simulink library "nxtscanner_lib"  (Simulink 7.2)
settings: Solver=ode45  StartTime=0.0  StopTime=10.0  RelTol=1e-3
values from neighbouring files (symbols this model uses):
  ERROR_001_SOUND_FREQ = 880    [mode_control_prm.m]
  ERROR_002_SOUND_FREQ = 220    [mode_control_prm.m]
  ERROR_SOUND_DUR = 3000    [mode_control_prm.m]
  ERROR_SOUND_VOL = 20    [mode_control_prm.m]
undefined symbols (not defined in the file or in its folder): BACKLASH_ADJUST, Enum, ErrorCodeEnum, FeedModeEnum, RELEASE_TOUCH_SENSOR, SCAN_EDGE, SCAN_F_TIMEOUT, SCAN_INITIALIZE_PWM, SCAN_INITIALIZE_TIMEOUT, SCAN_L_MAX_PWM, SCAN_L_MIN_PWM, SCAN_L_TIMEOUT, SCAN_R_MAX_PWM, SCAN_R_MIN_PWM, SCAN_R_TIMEOUT, SCAN_START, ScanModeEnum

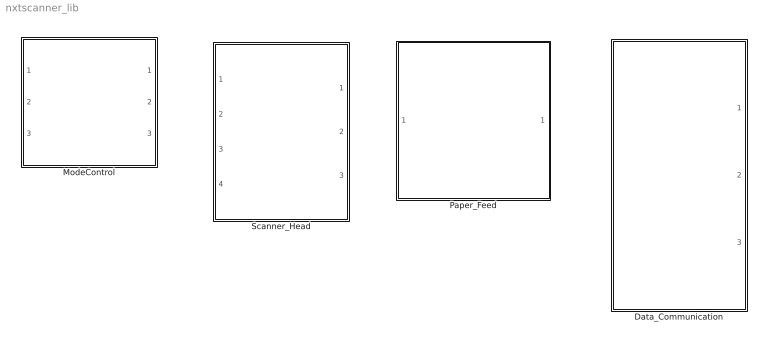
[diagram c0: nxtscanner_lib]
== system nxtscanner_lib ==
  Data_Communication : Subsystem
  ModeControl : Subsystem  TreatAsAtomicUnit=on
  Paper_Feed : Subsystem  TreatAsAtomicUnit=on
  Scanner_Head : Subsystem  TreatAsAtomicUnit=on

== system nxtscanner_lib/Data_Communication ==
  Mux : Mux  Inputs=3
  usb_communication_main : Stateflow chart
  usb_trans_data : Outport  OutDataType=sfix(16)  OutScaling=2^0
  request_event : Outport  Port=2  OutDataType=sfix(16)  OutScaling=2^0
  disconnect_event : Outport  Port=3  OutDataType=sfix(16)  OutScaling=2^0
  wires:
  usb_communication_main/5(DISCONNECT) -> disconnect_event/1
  usb_communication_main/4(COMUNICATION) -> request_event/1
  usb_communication_main/3(usb_send_data) -> Mux/3
  usb_communication_main/2(usb_send_number) -> Mux/2
  usb_communication_main/1(usb_send_status) -> Mux/1
  Mux/1 -> usb_trans_data/1

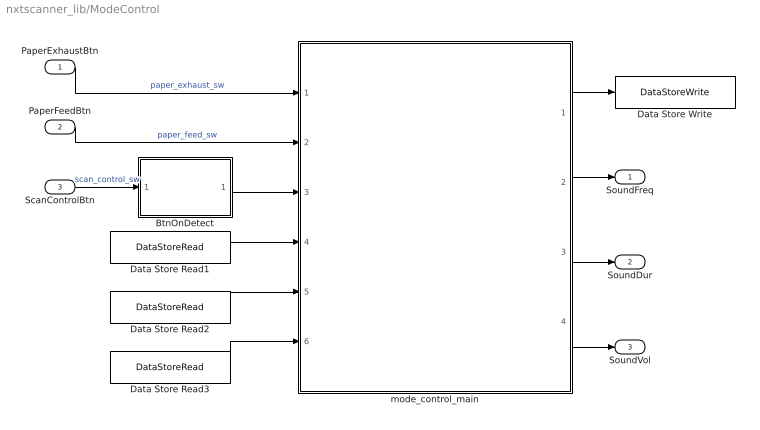
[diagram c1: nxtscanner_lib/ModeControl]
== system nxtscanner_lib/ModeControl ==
  PaperExhaustBtn : Inport
  PaperFeedBtn : Inport  Port=2
  ScanControlBtn : Inport  Port=3
  BtnOnDetect : Subsystem  TreatAsAtomicUnit=on
  Data Store Read1 : DataStoreRead  DataStoreName=ErrorCode  SampleTime=-1
  Data Store Read2 : DataStoreRead  DataStoreName=ScanMode  SampleTime=-1
  Data Store Read3 : DataStoreRead  DataStoreName=FeedMode  SampleTime=-1
  Data Store Write : DataStoreWrite  DataStoreName=ControlMode  SampleTime=-1
  mode_control_main : Stateflow chart
  SoundFreq : Outport  OutDataType=sfix(16)  OutScaling=2^0
  SoundDur : Outport  Port=2  OutDataType=sfix(16)  OutScaling=2^0
  SoundVol : Outport  Port=3  OutDataType=sfix(16)  OutScaling=2^0
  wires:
  Data Store Read3/1 -> mode_control_main/6(FeedMode)
  Data Store Read2/1 -> mode_control_main/5(ScanMode)
  mode_control_main/4(SoundVol) -> SoundVol/1
  mode_control_main/3(SoundDur) -> SoundDur/1
  mode_control_main/2(SoundFreq) -> SoundFreq/1
  BtnOnDetect/1(off2on) -> mode_control_main/3(ScanControl)
  ScanControlBtn/1 -> BtnOnDetect/1(button)  "scan_control_sw"
  PaperExhaustBtn/1 -> mode_control_main/1(PaperExhaustBtn)  "paper_exhaust_sw"
  PaperFeedBtn/1 -> mode_control_main/2(PaperFeedBtn)  "paper_feed_sw"
  Data Store Read1/1 -> mode_control_main/4(ErrorCode)
  mode_control_main/1(ControlMode) -> Data Store Write/1

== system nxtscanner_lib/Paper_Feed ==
  Encoder : Inport  OutDataType=sfix(16)  OutScaling=2^0
  Chart : Stateflow chart
  Counter_For_Error : Subsystem  TreatAsAtomicUnit=on
  Data Store Memory : DataStoreMemory  DataStoreName=ROTOR_FLAG  ReadBeforeWriteMsg=warning  WriteAfterWriteMsg=warning  WriteAfterReadMsg=warning  DataType=boolean  OutDataType=sfix(16)  OutScaling=2^0  OutDataTypeStr=boolean
  Data Store Memory1 : DataStoreMemory  DataStoreName=ROTOR_INIT  ReadBeforeWriteMsg=warning  WriteAfterWriteMsg=warning  WriteAfterReadMsg=warning  DataType=int32  OutDataType=sfix(16)  OutScaling=2^0  OutDataTypeStr=int32
  Data Store Write : DataStoreWrite  DataStoreName=ErrorCode  SampleTime=-1
  PWM : Outport  OutDataType=sfix(16)  OutScaling=2^0
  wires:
  Counter_For_Error/1(ErrorCode) -> Data Store Write/1
  Chart/2(ErrDetect) -> Counter_For_Error/Enable
  Encoder/1 -> Counter_For_Error/1(Encoder), Chart/1(Encoder)
  Chart/1(PWM) -> PWM/1

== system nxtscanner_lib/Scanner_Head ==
  Touch : Inport
  Encoder : Inport  Port=2
  LightSensor : Inport  Port=3
  SystemClock : Inport  Port=4
  scanner_head_main : Stateflow chart
  PWM : Outport  OutDataType=sfix(16)  OutScaling=2^0
  now_position : Outport  Port=2  OutDataType=sfix(16)  OutScaling=2^0
  encoder_base : Outport  Port=3  OutDataType=sfix(16)  OutScaling=2^0
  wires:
  SystemClock/1 -> scanner_head_main/4(system_clock_in)  "systick_ms"
  scanner_head_main/3(encoder_base) -> encoder_base/1
  scanner_head_main/2(now_position) -> now_position/1
  scanner_head_main/1(pwm_out) -> PWM/1
  LightSensor/1 -> scanner_head_main/3(lightsensor_in)  "light_data"
  Encoder/1 -> scanner_head_main/2(encoder_in)  "scanner_head_rev"
  Touch/1 -> scanner_head_main/1(touch_in)  "scanner_head_reset_sw"

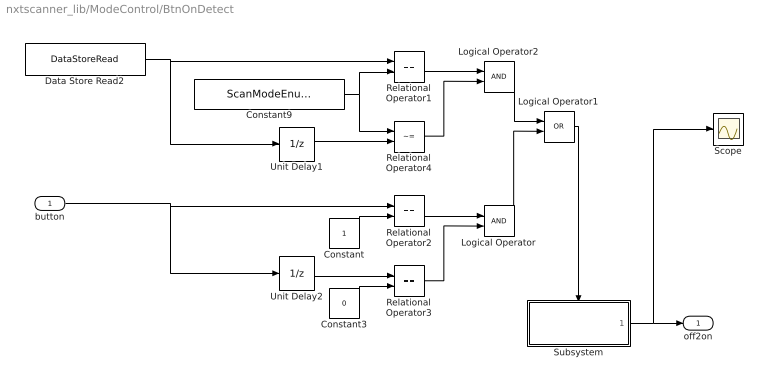
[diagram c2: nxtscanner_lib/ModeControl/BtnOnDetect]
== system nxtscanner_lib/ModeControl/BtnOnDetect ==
  button : Inport  OutDataType=sfix(16)  OutScaling=2^0
  Constant : Constant  OutDataTypeMode=uint8  OutDataType=sfix(16)  OutScaling=2^0  OutDataTypeStr=uint8
  Constant3 : Constant  Value=0  OutDataTypeMode=uint8  OutDataType=sfix(16)  OutScaling=2^0  OutDataTypeStr=uint8
  Constant9 : Constant  Value=ScanModeEnum.SCAN_INIT  OutDataTypeMode=Specify via dialog  OutDataType=Enum:ScanModeEnum  ConRadixGroup=Best Precision: Vector-wise  OutDataTypeStr=Enum:ScanModeEnum
  Data Store Read2 : DataStoreRead  DataStoreName=ScanMode  SampleTime=-1
  Logical Operator : Logic  AllPortsSameDT=off  OutDataTypeMode=boolean  OutDataTypeStr=boolean
  Logical Operator1 : Logic  Operator=OR  AllPortsSameDT=off  OutDataTypeMode=boolean  OutDataTypeStr=boolean
  Logical Operator2 : Logic  AllPortsSameDT=off  OutDataTypeMode=boolean  OutDataTypeStr=boolean
  Relational Operator1 : RelationalOperator  Operator===  LogicOutDataTypeMode=boolean  OutDataTypeStr=boolean
  Relational Operator2 : RelationalOperator  Operator===  LogicOutDataTypeMode=boolean  OutDataTypeStr=boolean
  Relational Operator3 : RelationalOperator  Operator===  LogicOutDataTypeMode=boolean  OutDataTypeStr=boolean
  Relational Operator4 : RelationalOperator  Operator=~=  LogicOutDataTypeMode=boolean  OutDataTypeStr=boolean
  Scope : Scope
  Subsystem : Subsystem  TreatAsAtomicUnit=on
  Unit Delay1 : UnitDelay  X0=ScanModeEnum.SCAN_INIT  SampleTime=-1
  Unit Delay2 : UnitDelay  SampleTime=-1
  off2on : Outport  OutDataType=sfix(16)  OutScaling=2^0
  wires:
  Subsystem/1(Out1) -> off2on/1, Scope/1
  Unit Delay1/1 -> Relational Operator4/2
  button/1 -> Relational Operator2/1, Unit Delay2/1
  Unit Delay2/1 -> Relational Operator3/1
  Relational Operator2/1 -> Logical Operator/1
  Relational Operator3/1 -> Logical Operator/2
  Constant/1 -> Relational Operator2/2
  Constant3/1 -> Relational Operator3/2
  Logical Operator1/1 -> Subsystem/Enable
  Logical Operator/1 -> Logical Operator1/2
  Data Store Read2/1 -> Unit Delay1/1, Relational Operator1/1
  Relational Operator1/1 -> Logical Operator2/1
  Logical Operator2/1 -> Logical Operator1/1
  Constant9/1 -> Relational Operator4/1, Relational Operator1/2
  Relational Operator4/1 -> Logical Operator2/2

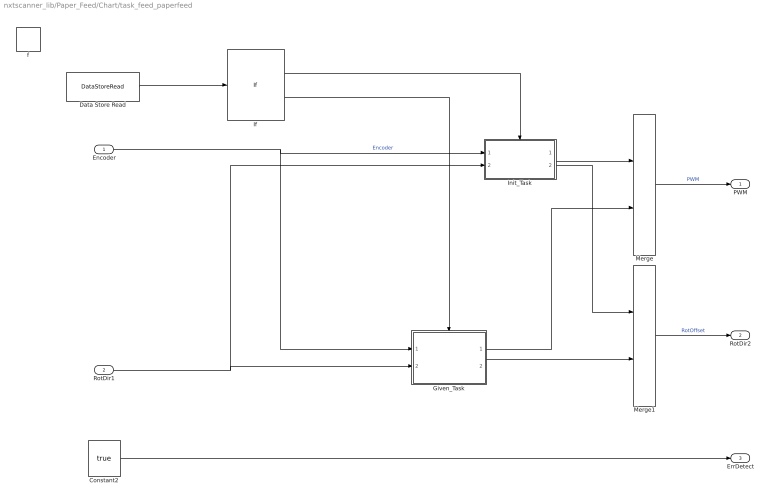
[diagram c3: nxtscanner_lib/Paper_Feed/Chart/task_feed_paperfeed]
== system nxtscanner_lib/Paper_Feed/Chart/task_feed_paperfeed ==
  Encoder : Inport  OutDataType=sfix(16)  OutScaling=2^0
  RotDir1 : Inport  Port=2  DataType=boolean  OutDataTypeStr=boolean
  f : TriggerPort  TriggerType=function-call  StatesWhenEnabling=reset
  Constant2 : Constant  Value=true  OutDataTypeMode=boolean  OutDataType=sfix(16)  OutScaling=2^0  OutDataTypeStr=boolean  SampleTime=-1
  Data Store Read : DataStoreRead  DataStoreName=ROTOR_FLAG  SampleTime=-1
  Given_Task : Subsystem  TreatAsAtomicUnit=on
  If : If  IfExpression=~u1
  Init_Task : Subsystem  TreatAsAtomicUnit=on
  Merge : Merge
  Merge1 : Merge
  PWM : Outport  OutDataType=sfix(16)  OutScaling=2^0
  RotDir2 : Outport  Port=2
  ErrDetect : Outport  Port=3  InitialOutput=0
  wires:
  Constant2/1 -> ErrDetect/1
  Init_Task/2(RotOffset1) -> Merge1/1
  Given_Task/1(PWM) -> Merge/2
  Given_Task/2(RotOffset1) -> Merge1/2
  Merge1/1 -> RotDir2/1  "RotOffset"
  RotDir1/1 -> Init_Task/2(RotOffset), Given_Task/2(RotOffset)
  Merge/1 -> PWM/1  "PWM"
  Init_Task/1(PWM) -> Merge/1
  Encoder/1 -> Given_Task/1(Encoder), Init_Task/1(Encoder)  "Encoder"
  If/2 -> Given_Task/Action
  If/1 -> Init_Task/Action
  Data Store Read/1 -> If/1

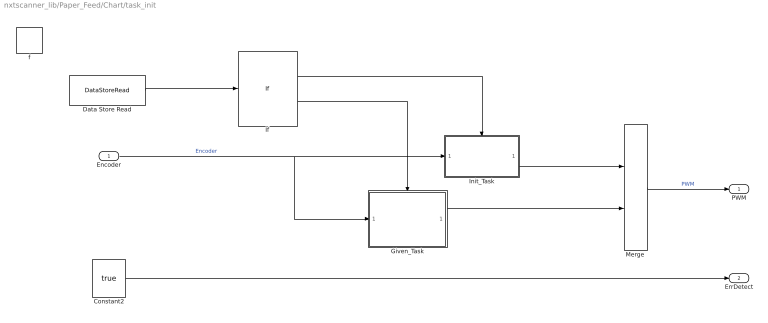
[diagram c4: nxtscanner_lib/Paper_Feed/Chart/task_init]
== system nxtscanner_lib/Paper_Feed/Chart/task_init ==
  Encoder : Inport  OutDataType=sfix(16)  OutScaling=2^0
  f : TriggerPort  TriggerType=function-call  StatesWhenEnabling=reset
  Constant2 : Constant  Value=true  OutDataTypeMode=boolean  OutDataType=sfix(16)  OutScaling=2^0  OutDataTypeStr=boolean  SampleTime=-1
  Data Store Read : DataStoreRead  DataStoreName=ROTOR_FLAG  SampleTime=-1
  Given_Task : Subsystem  TreatAsAtomicUnit=on
  If : If  IfExpression=~u1
  Init_Task : Subsystem  TreatAsAtomicUnit=on
  Merge : Merge
  PWM : Outport
  ErrDetect : Outport  Port=2  InitialOutput=0
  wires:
  Constant2/1 -> ErrDetect/1
  Given_Task/1(PWM) -> Merge/2
  Merge/1 -> PWM/1  "PWM"
  Init_Task/1(PWM) -> Merge/1
  Encoder/1 -> Given_Task/1(Encoder), Init_Task/1(Encoder)  "Encoder"
  If/2 -> Given_Task/Action
  If/1 -> Init_Task/Action
  Data Store Read/1 -> If/1

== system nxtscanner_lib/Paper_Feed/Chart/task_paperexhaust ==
  f : TriggerPort  TriggerType=function-call  StatesWhenEnabling=reset
  Constant : Constant  Value=-100  OutDataTypeMode=int8  OutDataType=sfix(16)  OutScaling=2^0  OutDataTypeStr=int8  SampleTime=-1
  Constant1 : Constant  Value=true  OutDataTypeMode=boolean  OutDataType=sfix(16)  OutScaling=2^0  OutDataTypeStr=boolean  SampleTime=-1
  Constant2 : Constant  Value=true  OutDataTypeMode=boolean  OutDataType=sfix(16)  OutScaling=2^0  OutDataTypeStr=boolean  SampleTime=-1
  PWM : Outport  OutDataType=sfix(16)  OutScaling=2^0  InitialOutput=0
  RotDir : Outport  Port=2  InitialOutput=0
  ErrDetect : Outport  Port=3  InitialOutput=0
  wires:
  Constant2/1 -> ErrDetect/1
  Constant1/1 -> RotDir/1
  Constant/1 -> PWM/1  "PWM"

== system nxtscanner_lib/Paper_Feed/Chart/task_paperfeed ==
  f : TriggerPort  TriggerType=function-call  StatesWhenEnabling=reset
  Constant : Constant  Value=100  OutDataTypeMode=int8  OutDataType=sfix(16)  OutScaling=2^0  OutDataTypeStr=int8  SampleTime=-1
  Constant1 : Constant  Value=false  OutDataTypeMode=boolean  OutDataType=sfix(16)  OutScaling=2^0  OutDataTypeStr=boolean  SampleTime=-1
  Constant2 : Constant  Value=true  OutDataTypeMode=boolean  OutDataType=sfix(16)  OutScaling=2^0  OutDataTypeStr=boolean  SampleTime=-1
  PWM : Outport  OutDataType=sfix(16)  OutScaling=2^0  InitialOutput=0
  RotDir : Outport  Port=2  InitialOutput=0
  ErrDetect : Outport  Port=3  InitialOutput=0
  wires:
  Constant2/1 -> ErrDetect/1
  Constant1/1 -> RotDir/1
  Constant/1 -> PWM/1  "PWM"

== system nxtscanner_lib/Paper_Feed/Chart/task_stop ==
  f : TriggerPort  TriggerType=function-call  StatesWhenEnabling=reset
  Constant : Constant  Value=0  OutDataTypeMode=int8  OutDataType=sfix(16)  OutScaling=2^0  OutDataTypeStr=int8  SampleTime=-1
  Constant2 : Constant  Value=false  OutDataTypeMode=boolean  OutDataType=sfix(16)  OutScaling=2^0  OutDataTypeStr=boolean  SampleTime=-1
  PWM : Outport  OutDataType=sfix(16)  OutScaling=2^0  InitialOutput=0
  ErrDetect : Outport  Port=2  InitialOutput=0
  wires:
  Constant2/1 -> ErrDetect/1
  Constant/1 -> PWM/1  "PWM"

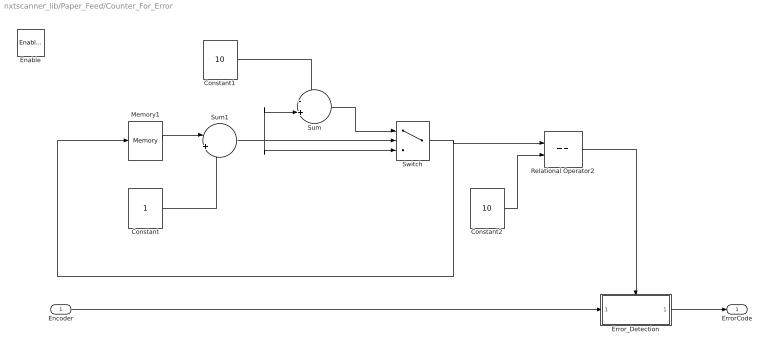
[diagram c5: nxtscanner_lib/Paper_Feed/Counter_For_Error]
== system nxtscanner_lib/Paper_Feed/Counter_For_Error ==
  Encoder : Inport  OutDataType=sfix(16)  OutScaling=2^0
  Enable : EnablePort  StatesWhenEnabling=reset
  Constant : Constant  OutDataTypeMode=uint8  OutDataType=sfix(16)  OutScaling=2^0  OutDataTypeStr=uint8  SampleTime=-1
  Constant1 : Constant  Value=10  OutDataTypeMode=uint8  OutDataType=sfix(16)  OutScaling=2^0  OutDataTypeStr=uint8  SampleTime=-1
  Constant2 : Constant  Value=10  OutDataTypeMode=uint8  OutDataType=sfix(16)  OutScaling=2^0  OutDataTypeStr=uint8  SampleTime=-1
  Error_Detection : Subsystem  TreatAsAtomicUnit=on
  Memory1 : Memory  InheritSampleTime=on
  Relational Operator2 : RelationalOperator  Operator===  LogicOutDataTypeMode=boolean  OutDataTypeStr=boolean
  Sum : Sum  Inputs=-+|  OutDataType=sfix(16)  OutScaling=2^0
  Sum1 : Sum  Inputs=|++  OutDataType=sfix(16)  OutScaling=2^0
  Switch : Switch  Criteria=u2 > Threshold  Threshold=10  OutDataTypeMode=uint8  OutDataType=sfix(16)  OutScaling=2^0  OutDataTypeStr=uint8
  ErrorCode : Outport  OutDataType=sfix(16)  OutScaling=2^0  InitialOutput=ErrorCodeEnum.NO_ERROR
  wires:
  Constant2/1 -> Relational Operator2/2
  Sum/1 -> Switch/1
  Sum1/1 -> Switch/3, Sum/2, Switch/2
  Constant1/1 -> Sum/1
  Switch/1 -> Memory1/1, Relational Operator2/1
  Memory1/1 -> Sum1/1
  Relational Operator2/1 -> Error_Detection/Trigger
  Error_Detection/1(ErrorCode) -> ErrorCode/1
  Encoder/1 -> Error_Detection/1(Encoder)
  Constant/1 -> Sum1/2

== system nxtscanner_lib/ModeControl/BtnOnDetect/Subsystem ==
  Enable : EnablePort
  Constant1 : Constant  OutDataTypeMode=uint8  OutDataType=sfix(16)  OutScaling=2^0  OutDataTypeStr=uint8
  Constant3 : Constant  Value=0  OutDataTypeMode=uint8  OutDataType=sfix(16)  OutScaling=2^0  OutDataTypeStr=uint8
  Switch : Switch  Threshold=0.5
  Unit Delay2 : UnitDelay  Orientation=left  SampleTime=-1
  Out1 : Outport  OutDataType=sfix(16)  OutScaling=2^0
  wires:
  Constant3/1 -> Switch/1
  Unit Delay2/1 -> Switch/2
  Constant1/1 -> Switch/3
  Switch/1 -> Unit Delay2/1, Out1/1

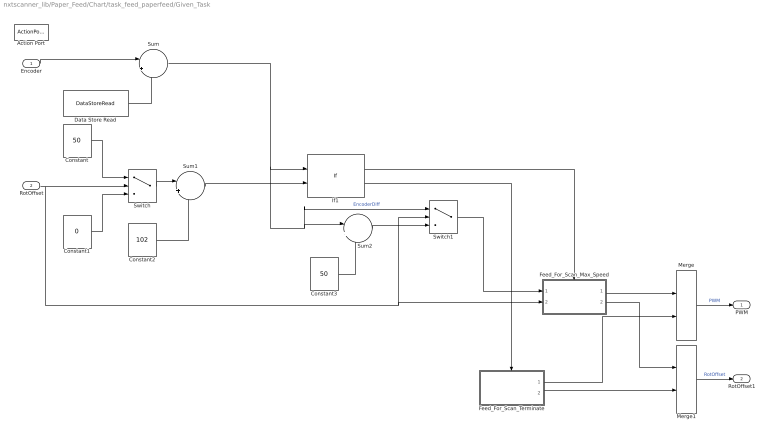
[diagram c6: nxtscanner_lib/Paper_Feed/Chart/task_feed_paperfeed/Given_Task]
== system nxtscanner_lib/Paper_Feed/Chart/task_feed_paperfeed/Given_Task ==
  Encoder : Inport  OutDataType=sfix(16)  OutScaling=2^0
  RotOffset : Inport  Port=2  OutDataType=sfix(16)  OutScaling=2^0
  Action Port : ActionPort
  Constant : Constant  Value=50  OutDataTypeMode=int32  OutDataType=sfix(16)  OutScaling=2^0  OutDataTypeStr=int32  SampleTime=-1
  Constant1 : Constant  Value=0  OutDataTypeMode=int32  OutDataType=sfix(16)  OutScaling=2^0  OutDataTypeStr=int32  SampleTime=-1
  Constant2 : Constant  Value=102  OutDataTypeMode=int32  OutDataType=sfix(16)  OutScaling=2^0  OutDataTypeStr=int32  SampleTime=-1
  Constant3 : Constant  Value=50  OutDataTypeMode=int32  OutDataType=sfix(16)  OutScaling=2^0  OutDataTypeStr=int32  SampleTime=-1
  Data Store Read : DataStoreRead  DataStoreName=ROTOR_INIT  SampleTime=-1
  Feed_For_Scan_Max_Speed : Subsystem  TreatAsAtomicUnit=on
  Feed_For_Scan_Terminate : Subsystem  TreatAsAtomicUnit=on
  If1 : If  NumInputs=2  IfExpression=u1 < u2
  Merge : Merge
  Merge1 : Merge
  Sum : Sum  Inputs=|+-  OutDataType=sfix(16)  OutScaling=2^0
  Sum1 : Sum  Inputs=|++  OutDataType=sfix(16)  OutScaling=2^0
  Sum2 : Sum  Inputs=|++  OutDataType=sfix(16)  OutScaling=2^0
  Switch : Switch  Criteria=u2 ~= 0  OutDataType=sfix(16)  OutScaling=2^0
  Switch1 : Switch  Criteria=u2 ~= 0  OutDataType=sfix(16)  OutScaling=2^0
  PWM : Outport  OutDataType=sfix(16)  OutScaling=2^0
  RotOffset1 : Outport  Port=2  OutDataType=sfix(16)  OutScaling=2^0
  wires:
  Sum2/1 -> Switch1/3
  Switch1/1 -> Feed_For_Scan_Max_Speed/1(EncoderDiff)
  Constant3/1 -> Sum2/2
  Sum1/1 -> If1/2
  Feed_For_Scan_Terminate/2(RotOffset) -> Merge1/2
  Feed_For_Scan_Max_Speed/2(RotOffset1) -> Merge1/1
  Feed_For_Scan_Terminate/1(PWM) -> Merge/2
  Feed_For_Scan_Max_Speed/1(PWM) -> Merge/1
  Constant1/1 -> Switch/3
  Constant/1 -> Switch/1
  Merge1/1 -> RotOffset1/1  "RotOffset"
  Constant2/1 -> Sum1/2
  Switch/1 -> Sum1/1
  RotOffset/1 -> Switch1/2, Feed_For_Scan_Max_Speed/2(RotOffset), Switch/2
  Merge/1 -> PWM/1  "PWM"
  If1/2 -> Feed_For_Scan_Terminate/Action
  If1/1 -> Feed_For_Scan_Max_Speed/Action
  Encoder/1 -> Sum/1
  Sum/1 -> Switch1/1, Sum2/1, If1/1  "EncoderDiff"
  Data Store Read/1 -> Sum/2

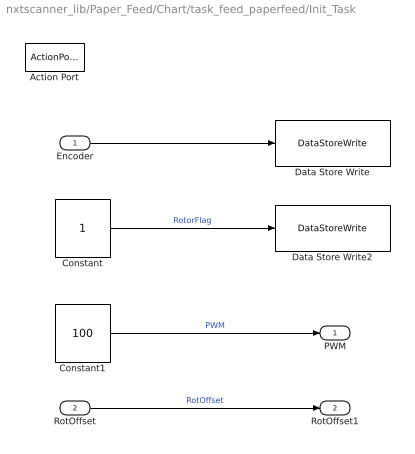
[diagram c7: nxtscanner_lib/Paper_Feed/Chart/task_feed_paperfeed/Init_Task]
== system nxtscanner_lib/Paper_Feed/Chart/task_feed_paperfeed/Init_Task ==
  Encoder : Inport  OutDataType=sfix(16)  OutScaling=2^0
  RotOffset : Inport  Port=2  OutDataType=sfix(16)  OutScaling=2^0
  Action Port : ActionPort
  Constant : Constant  OutDataTypeMode=boolean  OutDataType=sfix(16)  OutScaling=2^0  OutDataTypeStr=boolean  SampleTime=-1
  Constant1 : Constant  Value=100  OutDataTypeMode=int8  OutDataType=sfix(16)  OutScaling=2^0  OutDataTypeStr=int8  SampleTime=-1
  Data Store Write : DataStoreWrite  DataStoreName=ROTOR_INIT  SampleTime=-1
  Data Store Write2 : DataStoreWrite  DataStoreName=ROTOR_FLAG  SampleTime=-1
  PWM : Outport  OutDataType=sfix(16)  OutScaling=2^0  InitialOutput=100
  RotOffset1 : Outport  Port=2
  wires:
  RotOffset/1 -> RotOffset1/1  "RotOffset"
  Constant1/1 -> PWM/1  "PWM"
  Constant/1 -> Data Store Write2/1  "RotorFlag"
  Encoder/1 -> Data Store Write/1

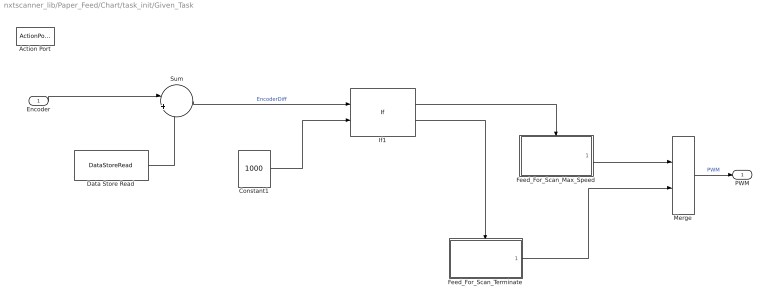
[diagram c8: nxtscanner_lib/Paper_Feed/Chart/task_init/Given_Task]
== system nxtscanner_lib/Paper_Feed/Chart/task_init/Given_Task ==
  Encoder : Inport  OutDataType=sfix(16)  OutScaling=2^0
  Action Port : ActionPort
  Constant1 : Constant  Value=1000  OutDataTypeMode=int32  OutDataType=sfix(16)  OutScaling=2^0  OutDataTypeStr=int32  SampleTime=-1
  Data Store Read : DataStoreRead  DataStoreName=ROTOR_INIT  SampleTime=-1
  Feed_For_Scan_Max_Speed : Subsystem  TreatAsAtomicUnit=on
  Feed_For_Scan_Terminate : Subsystem  TreatAsAtomicUnit=on
  If1 : If  NumInputs=2  IfExpression=u1 < u2
  Merge : Merge
  Sum : Sum  Inputs=|+-  OutDataType=sfix(16)  OutScaling=2^0
  PWM : Outport  OutDataType=sfix(16)  OutScaling=2^0
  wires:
  Feed_For_Scan_Terminate/1(PWM) -> Merge/2
  Constant1/1 -> If1/2
  Feed_For_Scan_Max_Speed/1(PWM) -> Merge/1
  Merge/1 -> PWM/1  "PWM"
  If1/2 -> Feed_For_Scan_Terminate/Action
  If1/1 -> Feed_For_Scan_Max_Speed/Action
  Encoder/1 -> Sum/1
  Sum/1 -> If1/1  "EncoderDiff"
  Data Store Read/1 -> Sum/2

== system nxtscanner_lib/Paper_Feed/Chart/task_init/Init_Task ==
  Encoder : Inport  OutDataType=sfix(16)  OutScaling=2^0
  Action Port : ActionPort
  Constant : Constant  OutDataTypeMode=boolean  OutDataType=sfix(16)  OutScaling=2^0  OutDataTypeStr=boolean  SampleTime=-1
  Constant1 : Constant  Value=100  OutDataTypeMode=int8  OutDataType=sfix(16)  OutScaling=2^0  OutDataTypeStr=int8  SampleTime=-1
  Data Store Write : DataStoreWrite  DataStoreName=ROTOR_INIT  SampleTime=-1
  Data Store Write2 : DataStoreWrite  DataStoreName=ROTOR_FLAG  SampleTime=-1
  PWM : Outport  OutDataType=sfix(16)  OutScaling=2^0  InitialOutput=100
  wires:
  Encoder/1 -> Data Store Write/1
  Constant1/1 -> PWM/1  "PWM"
  Constant/1 -> Data Store Write2/1  "RotorFlag"

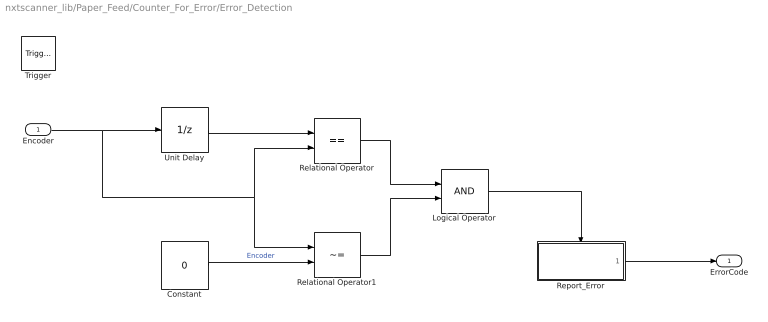
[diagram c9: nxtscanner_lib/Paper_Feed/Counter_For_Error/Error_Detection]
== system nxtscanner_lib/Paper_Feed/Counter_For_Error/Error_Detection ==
  Encoder : Inport  OutDataType=sfix(16)  OutScaling=2^0
  Trigger : TriggerPort
  Constant : Constant  Value=0  OutDataTypeMode=int8  OutDataType=sfix(16)  OutScaling=2^0  OutDataTypeStr=int8  SampleTime=-1
  Logical Operator : Logic  AllPortsSameDT=off  OutDataTypeMode=boolean  OutDataTypeStr=boolean
  Relational Operator : RelationalOperator  Operator===  LogicOutDataTypeMode=boolean  OutDataTypeStr=boolean
  Relational Operator1 : RelationalOperator  Operator=~=  LogicOutDataTypeMode=boolean  OutDataTypeStr=boolean
  Report_Error : Subsystem  TreatAsAtomicUnit=on
  Unit Delay : UnitDelay  SampleTime=-1
  ErrorCode : Outport  OutDataType=sfix(16)  OutScaling=2^0
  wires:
  Constant/1 -> Relational Operator1/2  "Encoder"
  Encoder/1 -> Relational Operator/2, Relational Operator1/1, Unit Delay/1
  Relational Operator/1 -> Logical Operator/1
  Relational Operator1/1 -> Logical Operator/2
  Unit Delay/1 -> Relational Operator/1
  Logical Operator/1 -> Report_Error/Enable
  Report_Error/1(ErrorCode) -> ErrorCode/1

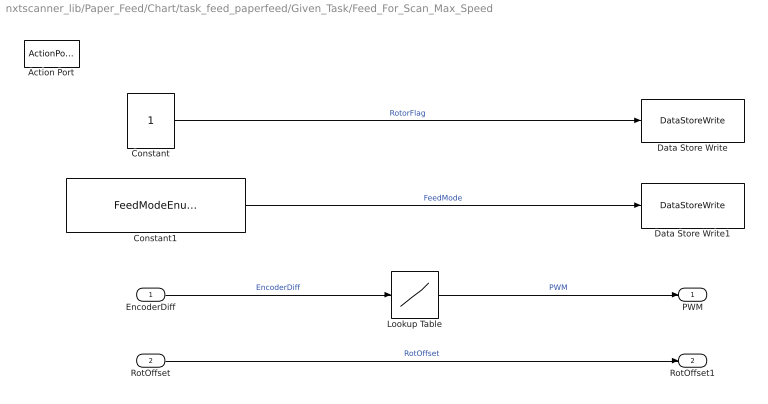
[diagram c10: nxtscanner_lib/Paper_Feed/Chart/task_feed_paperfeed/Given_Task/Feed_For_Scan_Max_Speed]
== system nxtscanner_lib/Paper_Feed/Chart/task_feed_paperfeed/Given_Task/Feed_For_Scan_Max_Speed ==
  EncoderDiff : Inport  OutDataType=sfix(16)  OutScaling=2^0
  RotOffset : Inport  Port=2  OutDataType=sfix(16)  OutScaling=2^0
  Action Port : ActionPort
  Constant : Constant  OutDataTypeMode=boolean  OutDataType=sfix(16)  OutScaling=2^0  OutDataTypeStr=boolean  SampleTime=-1
  Constant1 : Constant  Value=FeedModeEnum.FEED_PAPERFEED  OutDataTypeMode=Specify via dialog  OutDataType=Enum: FeedModeEnum  ConRadixGroup=Best Precision: Vector-wise  OutDataTypeStr=Enum: FeedModeEnum  SampleTime=-1
  Data Store Write : DataStoreWrite  DataStoreName=ROTOR_FLAG  SampleTime=-1
  Data Store Write1 : DataStoreWrite  DataStoreName=FeedMode  SampleTime=-1
  Lookup Table : Lookup  InputValues=int32(0:10:150)  Table=int8([100 100 100 100 100 100 77 45 35 25 18 13 10 8 4 4]);  LookUpMeth=Use Input Nearest  OutDataTypeMode=int8  OutDataType=sfix(16)  OutScaling=2^0  OutDataTypeStr=int8
  PWM : Outport  OutDataType=sfix(16)  OutScaling=2^0  InitialOutput=100
  RotOffset1 : Outport  Port=2
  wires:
  RotOffset/1 -> RotOffset1/1  "RotOffset"
  Lookup Table/1 -> PWM/1  "PWM"
  EncoderDiff/1 -> Lookup Table/1  "EncoderDiff"
  Constant1/1 -> Data Store Write1/1  "FeedMode"
  Constant/1 -> Data Store Write/1  "RotorFlag"

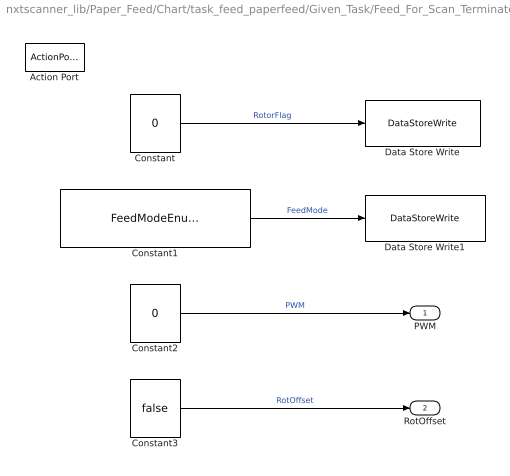
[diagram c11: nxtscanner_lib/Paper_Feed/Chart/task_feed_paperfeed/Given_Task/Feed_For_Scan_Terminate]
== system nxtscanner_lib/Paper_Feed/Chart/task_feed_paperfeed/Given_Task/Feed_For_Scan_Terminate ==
  Action Port : ActionPort
  Constant : Constant  Value=0  OutDataTypeMode=boolean  OutDataType=sfix(16)  OutScaling=2^0  OutDataTypeStr=boolean  SampleTime=-1
  Constant1 : Constant  Value=FeedModeEnum.FEED_IDLE  OutDataTypeMode=Specify via dialog  OutDataType=Enum: FeedModeEnum  ConRadixGroup=Best Precision: Vector-wise  OutDataTypeStr=Enum: FeedModeEnum  SampleTime=-1
  Constant2 : Constant  Value=0  OutDataTypeMode=int8  OutDataType=sfix(16)  OutScaling=2^0  OutDataTypeStr=int8  SampleTime=-1
  Constant3 : Constant  Value=false  OutDataTypeMode=boolean  OutDataType=sfix(16)  OutScaling=2^0  OutDataTypeStr=boolean  SampleTime=-1
  Data Store Write : DataStoreWrite  DataStoreName=ROTOR_FLAG  SampleTime=-1
  Data Store Write1 : DataStoreWrite  DataStoreName=FeedMode  SampleTime=-1
  PWM : Outport  OutDataType=sfix(16)  OutScaling=2^0  InitialOutput=0
  RotOffset : Outport  Port=2  InitialOutput=0
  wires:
  Constant3/1 -> RotOffset/1  "RotOffset"
  Constant2/1 -> PWM/1  "PWM"
  Constant1/1 -> Data Store Write1/1  "FeedMode"
  Constant/1 -> Data Store Write/1  "RotorFlag"

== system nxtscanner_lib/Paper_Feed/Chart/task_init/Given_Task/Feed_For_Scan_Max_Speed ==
  Action Port : ActionPort
  Constant : Constant  OutDataTypeMode=boolean  OutDataType=sfix(16)  OutScaling=2^0  OutDataTypeStr=boolean  SampleTime=-1
  Constant1 : Constant  Value=100  OutDataTypeMode=int8  OutDataType=sfix(16)  OutScaling=2^0  OutDataTypeStr=int8  SampleTime=-1
  Constant2 : Constant  Value=FeedModeEnum.FEED_INIT  OutDataTypeMode=Specify via dialog  OutDataType=Enum: FeedModeEnum  ConRadixGroup=Best Precision: Vector-wise  OutDataTypeStr=Enum: FeedModeEnum  SampleTime=-1
  Data Store Write : DataStoreWrite  DataStoreName=ROTOR_FLAG  SampleTime=-1
  Data Store Write1 : DataStoreWrite  DataStoreName=FeedMode  SampleTime=-1
  PWM : Outport  OutDataType=sfix(16)  OutScaling=2^0  InitialOutput=100
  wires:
  Constant2/1 -> Data Store Write1/1  "FeedMode"
  Constant1/1 -> PWM/1  "PWM"
  Constant/1 -> Data Store Write/1  "RotorFlag"

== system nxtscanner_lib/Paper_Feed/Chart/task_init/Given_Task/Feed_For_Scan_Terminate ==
  Action Port : ActionPort
  Constant : Constant  Value=0  OutDataTypeMode=boolean  OutDataType=sfix(16)  OutScaling=2^0  OutDataTypeStr=boolean  SampleTime=-1
  Constant1 : Constant  Value=0  OutDataTypeMode=int8  OutDataType=sfix(16)  OutScaling=2^0  OutDataTypeStr=int8  SampleTime=-1
  Constant2 : Constant  Value=FeedModeEnum.FEED_IDLE  OutDataTypeMode=Specify via dialog  OutDataType=Enum: FeedModeEnum  ConRadixGroup=Best Precision: Vector-wise  OutDataTypeStr=Enum: FeedModeEnum  SampleTime=-1
  Data Store Write : DataStoreWrite  DataStoreName=ROTOR_FLAG  SampleTime=-1
  Data Store Write1 : DataStoreWrite  DataStoreName=FeedMode  SampleTime=-1
  PWM : Outport  OutDataType=sfix(16)  OutScaling=2^0  InitialOutput=100
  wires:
  Constant2/1 -> Data Store Write1/1  "FeedMode"
  Constant1/1 -> PWM/1  "PWM"
  Constant/1 -> Data Store Write/1  "RotorFlag"

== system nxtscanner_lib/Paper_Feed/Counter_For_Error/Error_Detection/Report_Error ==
  Enable : EnablePort
  Constant : Constant  Value=ErrorCodeEnum.ERROR_002  OutDataTypeMode=Specify via dialog  OutDataType=Enum:ErrorCodeEnum  ConRadixGroup=Best Precision: Vector-wise  OutDataTypeStr=Enum:ErrorCodeEnum  SampleTime=-1
  ErrorCode : Outport  OutDataType=sfix(16)  OutScaling=2^0
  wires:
  Constant/1 -> ErrorCode/1  "ErrorCode"

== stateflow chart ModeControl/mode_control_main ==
  state NORMAL/
    state IDLE/
      en:
      % no control
      ControlMode = IDLE;
    state PAPER_FEED/
      % paper feed button operation
      en:
      ControlMode = PAPERFEED;
    state PAPER_EXHAUST/
      % paper exhaust button operation
      en:
      ControlMode = PAPEREXHAUST;
    state SCAN_CONTROL/
      % scan control button operation
      en:
      ControlMode = SCAN;
    state INITIALIZE/
      en:
      % mecha initialize
      ControlMode = INITIALIZE;
    (default) -> INITIALIZE
    IDLE -> PAPER_FEED : [PaperFeedBtn == 1]
    PAPER_FEED -> IDLE : [PaperFeedBtn == 0]
    IDLE -> PAPER_EXHAUST : [PaperExhaustBtn == 1]
    PAPER_EXHAUST -> IDLE : [PaperExhaustBtn == 0]
    IDLE -> SCAN_CONTROL : [ScanControl == 1]
    SCAN_CONTROL -> INITIALIZE : [ScanControl == 0]
    INITIALIZE -> IDLE : [ScanMode == SCAN_IDLE && FeedMode == FEED_IDLE]
  state ERROR/
    % error job
    en:
    ControlMode = ERROR;
    % sound for system error
    SoundDur = ERROR_SOUND_DUR;
    SoundVol = ERROR_SOUND_VOL;
  NORMAL -> (junction 10) : [ErrorCode != NO_ERROR]
  (junction 10) -> (junction 11) : [ErrorCode == ERROR_001]
  (junction 11) -> (junction 12) : { % sound select SoundFreq = ERROR_001_SOUND_FREQ; }
  (junction 10) -> (junction 13) : { % sound select SoundFreq = ERROR_002_SOUND_FREQ; }
  (junction 12) -> (junction 13)
  (junction 13) -> ERROR
  (default) -> NORMAL

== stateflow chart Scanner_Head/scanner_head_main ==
  state paper_feed_init [function]
    (default) -> (junction 115)
  state scan_usb_stop [function]
    (default) -> (junction 68) : { pwm_out = 0; ScannerBuffer_Info[select]=FULL_UP; ScannerBuffer_Status[select] = status_maker(1, start_flg, 1, DIR_R); ScannerBuffer_Pnum[select] = packet_cnt + 1; }
  state SCAN_INIT_POSITION/
    en:
    % initial position serch for scanner head
    scan_environment();
    scan_timeover_set();
    scan_start_position_seek();
    du:
    scan_start_position_seek();
  state paper_feed [function]
    (junction 87) -> (junction 70) : { % paper feeding }
    (junction 78) -> (junction 70)
    (junction 89) -> (junction 78) : { % paper feed finished ScanMode = SCAN_SCAN; }
    (default) -> (junction 87)
    (junction 87) -> (junction 89) : [FeedMode == FEED_IDLE]
  state SCAN_ERROR/
    en:
    % system malfunction
    pwm_out = 0;
  state SCAN_ERROR_STOP/
    en:
    % scanner head system error
    scan_usb_stop();
    ErrorCode = ERROR_001;
  state scan_environment [function]
    (default) -> (junction 98) : { start_flg = 1; select = 0; line_cnt=0; line_end_flg = 0; packet_cnt = 0; scan_init_end_flg = 0; }
  state scan_init(arg_target_dir) [function]
    (junction 110) -> (junction 116) : { % for left-scanning start_position = encoder_in +BACKLASH_ADJUST; }
    (junction 123) -> (junction 110) : % request of scan direction [arg_target_dir == DIR_L]
    (junction 116) -> (junction 72)
    (junction 73) -> (junction 72) : { % for right-scanning(only after initialize) start_position = encoder_in -RELEASE_TOUCH_SENSOR -BACKLASH_ADJUST; }
    (junction 95) -> (junction 73) : [start_flg == 1]
    (default) -> (junction 123) : { line_end_flg = 0; packet_cnt = 0; ScanMode = SCAN_SCAN; encoder_base =SCAN_START; }
    (junction 123) -> (junction 95)
    (junction 95) -> (junction 118) : { % for right-scanning(nomaly) start_position = encoder_in -BACKLASH_ADJUST; }
    (junction 72) -> (junction 118)
  state out = status_maker(arg_elp, arg_start, arg_stop, arg_dir) [function]
    (junction 112) -> (junction 130) : { out = out + 16; }
    (junction 86) -> (junction 83) : { out = out + 4; }
    (junction 76) -> (junction 84)
    (junction 83) -> (junction 84)
    (junction 93) -> (junction 92)
    (junction 85) -> (junction 92)
    (junction 90) -> (junction 85) : { out = out + 8; }
    (junction 76) -> (junction 86) : [arg_stop == 1]
    (junction 92) -> (junction 76)
    (junction 93) -> (junction 90) : [arg_start == 1]
    (default) -> (junction 113) : { out = 1; }
    (junction 130) -> (junction 114)
    (junction 113) -> (junction 112) : [arg_elp == 1]
    (junction 114) -> (junction 93)
    (junction 113) -> (junction 114)
    (junction 84) -> (junction 152)
    (junction 150) -> (junction 151)
    (junction 152) -> (junction 151)
    (junction 153) -> (junction 150) : { out = out + 2; }
    (junction 152) -> (junction 153) : [arg_dir == 1]
  state scan_control_right [function]
    (default) -> (junction 139) : { % right-scanning now_position = start_position - encoder_in; pwm_out = get_pwm_value(DIR_R, now_position, SCAN_R_MAX_PWM, SCAN_R_MIN_PWM); }
    (junction 67) -> (junction 97) : % buffer full detection [ScannerBuffer_Number[select] >= 30]
    (junction 128) -> (junction 126) : { % send final packet line_end_flg = 1; line_cnt ++; ScannerBuffer_Info[select]=FULL_UP; packet_cnt ++; ScannerBuffer_Pnum[select] = packet_cnt; }
    (junction 79) -> (junction 81)
    (junction 126) -> (junction 71) : [line_cnt >=127]
    (junction 125) -> (junction 67) : { % next scan position encoder_base = encoder_base + 2; % store data ScannerBuffer_Data[select][ScannerBuffer_Number[select]] = lightsensor_in; ScannerBuffer_Number[select]++; ScannerBuffer_Info[select] = STORING; }
    (junction 99) -> (junction 96) : % edge detection [pwm_out == 0]
    (junction 71) -> (junction 81) : { ScannerBuffer_Status[select] = status_maker(1, start_flg, 1, DIR_R); ScanMode = SCAN_INIT; FINISH; }
    (junction 121) -> (junction 103)
    (junction 97) -> (junction 108) : { packet_cnt ++; ScannerBuffer_Info[select]=FULL_UP; ScannerBuffer_Status[select] = status_maker(0, start_flg, 0, DIR_R); ScannerBuffer_Pnum[select] = packet_cnt; start_flg=0; }
    (junction 119) -> (junction 101)
    (junction 101) -> (junction 102)
    (junction 102) -> (junction 79)
    (junction 81) -> (junction 80)
    (junction 107) -> (junction 101) : { % full of buffer1 select = 0; }
    (junction 108) -> (junction 102) : { % full of buffer0 select = 1; }
    (junction 108) -> (junction 107) : [select == 1]
    (junction 67) -> (junction 79)
    (junction 121) -> (junction 120) : [(now_position > SCAN_START && now_position > encoder_base)]
    (junction 139) -> (junction 99)
    (junction 99) -> (junction 121)
    (junction 120) -> (junction 124)
    (junction 124) -> (junction 125) : [now_position <= (SCAN_EDGE - SCAN_START)]
    (junction 126) -> (junction 80) : { ScannerBuffer_Status[select] = status_maker(1, start_flg, 0, DIR_R); }
    (junction 80) -> (junction 129)
    (junction 127) -> (junction 128) : [line_end_flg == 0]
    (junction 124) -> (junction 127)
    (junction 127) -> (junction 129)
    (junction 129) -> (junction 103)
    (junction 96) -> (junction 119) : { % right-scanning finished FeedMode = FEED_PAPERFEED; ScanMode = SCAN_FEED; }
    (junction 132) -> (junction 119)
    (junction 139) -> (junction 134) : [touch_in == 1 && now_position > 0]
    (junction 134) -> (junction 132) : { STOP; }
  state scan_start_position_seek [function]
    (junction 117) -> (junction 109) : { % initialize finished pwm_out = 0; ScanMode = SCAN_IDLE; scan_init_end_flg = 1; }
    (default) -> (junction 88)
    (junction 88) -> (junction 106)
    (junction 105) -> (junction 104) : { STOP; }
    (junction 88) -> (junction 117) : [touch_in == 1]
    (junction 104) -> (junction 111)
    (junction 106) -> (junction 111) : { % now moving pwm_out = SCAN_INITIALIZE_PWM; scan_timeover_check(SCAN_INITIALIZE_TIMEOUT, system_clock_in); }
    (junction 106) -> (junction 105) : [scan_init_end_flg == 1]
    (junction 109) -> (junction 104)
  state scan_timeover_set [function]
    (default) -> (junction 136) : { start_time = system_clock_in; }
  state INIT_ERROR_STOP/
    en:
    % error
    pwm_out = 0;
    ErrorCode = ERROR_001;
  state scan_timeover_check(arg_target_ms, arg_now_clock) [function]
    (junction 122) -> (junction 133) : [arg_target_ms < (arg_now_clock - start_time)]
    (junction 133) -> (junction 140) : { % time over STOP; }
    (junction 122) -> (junction 100)
    (default) -> (junction 122)
    (junction 140) -> (junction 100)
  state SCAN_NORMAL/
    state SCAN_RIGHT/
      % scanner head right-scanning
      en:
      scan_init(DIR_R);
      scan_timeover_set();
      scan_control_right();
      du:
      scan_control_right();
      scan_timeover_check(SCAN_R_TIMEOUT, system_clock_in);
    state SCAN_LEFT/
      % scanner head left-scanning
      en:
      scan_init(DIR_L);
      scan_timeover_set();
      scan_control_left();
      du:
      scan_control_left();
      scan_timeover_check(SCAN_L_TIMEOUT, system_clock_in);
    state PAPER_FEED_L/
      % paper feed at left edge
      en:
      paper_feed_init();
      scan_timeover_set();
      paper_feed();
      du:
      paper_feed();
      scan_timeover_check(SCAN_F_TIMEOUT, system_clock_in);
    SCAN_RIGHT -> SCAN_LEFT : [ScanMode == SCAN_FEED] {ScanMode = SCAN_SCAN;}
    (default) -> SCAN_RIGHT
    PAPER_FEED_L -> SCAN_RIGHT : [ScanMode == SCAN_SCAN]
    SCAN_LEFT -> PAPER_FEED_L : [ScanMode == SCAN_FEED]
  state pwm = get_pwm_value(arg_dir, arg_position, arg_max, arg_min) [function]
    (junction 91) -> (junction 94)
    (junction 91) -> (junction 66) : [arg_position < 0]
    (junction 75) -> (junction 141) : { % over position pwm = 0; }
    (junction 74) -> (junction 77) : { % sine change for right-scanning pwm = (-1)*pwm; }
    (junction 148) -> (junction 74) : [arg_dir == 0]
    (junction 94) -> (junction 75) : [arg_position > SCAN_EDGE]
    (default) -> (junction 91) : /* scanner head speed control */
    (junction 94) -> (junction 131)
    (junction 131) -> (junction 135) : { % accel & constant speed pwm = arg_max; }
    (junction 131) -> (junction 138) : [arg_position > (SCAN_EDGE - 60)]
    (junction 66) -> (junction 137) : { % before start position pwm = arg_max; }
    (junction 138) -> (junction 143) : { % brake control pwm = arg_min; }
    (junction 143) -> (junction 135)
    (junction 137) -> (junction 141)
    (junction 141) -> (junction 143)
    (junction 77) -> (junction 142)
    (junction 135) -> (junction 148)
    (junction 148) -> (junction 142)
  state scan_control_left [function]
    (junction 147) -> (junction 149) : { % finish left-scanning(only move) %FeedMode = FEED_IDLE; ScanMode = SCAN_FEED; }
    (junction 82) -> (junction 149)
    (junction 146) -> (junction 69)
    (default) -> (junction 144) : { % left-scanning now_position = encoder_in - start_position; pwm_out = get_pwm_value(DIR_L, now_position, SCAN_L_MAX_PWM, SCAN_L_MIN_PWM); }
    (junction 149) -> (junction 69)
    (junction 144) -> (junction 145) : [touch_in == 1 && now_position > 0]
    (junction 144) -> (junction 146)
    (junction 145) -> (junction 82) : { RUNTIME_ERROR; }
    (junction 146) -> (junction 147) : % edge detection [pwm_out == 0]
  state RUNTIME_ERROR_STOP/
    en:
    % for polyspace demonstration
    pwm_out = 7;
    ErrorCode = ERROR_001;
    ScannerBuffer_Info[select]=FULL_UP;
    ScannerBuffer_Status[select] = status_maker(1, start_flg, 1, DIR_L);
    ScannerBuffer_Pnum[select] = polyspace[pwm_out];
  SCAN_INIT_POSITION -> SCAN_NORMAL : [ControlMode == SCAN && ScanMode == SCAN_IDLE]
  SCAN_NORMAL -> SCAN_ERROR : [ControlMode == ERROR] { scan_usb_stop(); }
  (default) -> SCAN_INIT_POSITION
  SCAN_NORMAL -> SCAN_INIT_POSITION : [ControlMode != ERROR && ControlMode != SCAN] { scan_usb_stop(); }
  SCAN_INIT_POSITION -> SCAN_ERROR : [ControlMode == ERROR]
  SCAN_NORMAL -> RUNTIME_ERROR_STOP : RUNTIME_ERROR
  SCAN_NORMAL -> SCAN_INIT_POSITION : FINISH
  INIT_ERROR_STOP -> SCAN_ERROR : [ControlMode == ERROR]
  SCAN_INIT_POSITION -> INIT_ERROR_STOP : STOP
  SCAN_NORMAL -> SCAN_ERROR_STOP : STOP

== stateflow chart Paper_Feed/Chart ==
  state [PWM,RotDir,ErrDetect] = task_paperfeed [function]
  state [PWM,RotDir,ErrDetect] = task_paperexhaust [function]
  state [PWM,ErrDetect] = task_stop [function]
  state [PWM,RotDir2,ErrDetect] = task_feed_paperfeed(Encoder,RotDir1) [function]
  state [PWM,ErrDetect] = task_init(Encoder) [function]
  (junction 345) -> (junction 349)
  (junction 343) -> (junction 347)
  (junction 348) -> (junction 350) : {[PWM, ErrDetect] = task_stop();}
  (junction 353) -> (junction 345)
  (junction 352) -> (junction 347) : {[PWM, RotDir, ErrDetect]= task_paperexhaust();}
  (junction 349) -> (junction 348) : [ControlMode == IDLE]
  (junction 344) -> (junction 357) : [FeedMode == FEED_PAPERFEED]
  (junction 345) -> (junction 352) : [ControlMode == PAPEREXHAUST]
  (junction 346) -> (junction 343) : {[PWM, RotDir, ErrDetect] = task_paperfeed();}
  (default) -> (junction 362)
  (junction 344) -> (junction 356) : {[PWM, ErrDetect] = task_stop();}
  (junction 353) -> (junction 346) : [ControlMode == PAPERFEED]
  (junction 359) -> (junction 358) : [ControlMode == ERROR]
  (junction 347) -> (junction 350)
  (junction 356) -> (junction 354)
  (junction 355) -> (junction 356)
  (junction 357) -> (junction 355) : {[PWM, RotDir, ErrDetect] = ... task_feed_paperfeed(Encoder, RotDir);}
  (junction 349) -> (junction 359)
  (junction 350) -> (junction 351)
  (junction 358) -> (junction 351) : {[PWM, ErrDetect] = task_stop();}
  (junction 359) -> (junction 344)
  (junction 360) -> (junction 363)
  (junction 365) -> (junction 360) : {[PWM, ErrDetect] = task_init(Encoder);}
  (junction 354) -> (junction 361)
  (junction 362) -> (junction 364) : [ControlMode == INITIALIZE]
  (junction 363) -> (junction 343)
  (junction 362) -> (junction 353)
  (junction 364) -> (junction 365) : [FeedMode == FEED_INIT]
  (junction 364) -> (junction 363) : {[PWM, ErrDetect] = task_stop();}
  (junction 351) -> (junction 354)

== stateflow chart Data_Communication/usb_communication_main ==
  state usb_communication(arg_select_buffer) [function]
    (junction 441) -> (junction 437)
    (default) -> (junction 439) : { %status上位バイトはゼロ usb_send_status[1] = 0; usb_send_status[0] = ScannerBuffer_Status[arg_select_buffer]; %number上位バイトはゼロ usb_send_number[1] = 0; usb_send_number[0] = ScannerBuffer_Number[arg_select_buffer]; }
    (junction 439) -> (junction 441) : { index = 0; }
    (junction 441) -> (junction 440) : [index < 30]
    (junction 440) -> (junction 430) : { % uint16⇒uint8に分割 usb_send_data[index*2+1] = (ScannerBuffer_Data[arg_select_buffer][index] & 0xFF00) >> 8; usb_send_data[index*2] = ScannerBuffer_Data[arg_select_buffer][index] & 0x00FF; }
    (junction 430) -> (junction 441) : { index++; }
  state init_buffer(arg_select_buf) [function]
    (junction 429) -> (junction 427)
    (junction 434) -> (junction 428) : { ScannerBuffer_Data[arg_select_buf][index] = 0; }
    (junction 431) -> (junction 432) : { ScannerBuffer_Info[arg_select_buf] = TRANS_FINISH; ScannerBuffer_Status[arg_select_buf] = 0; ScannerBuffer_Number[arg_select_buf] = 0; ScannerBuffer_Pnum[arg_select_buf] = 0; }
    (junction 428) -> (junction 429) : { index++; }
    (junction 432) -> (junction 429) : { index = 0; }
    (junction 429) -> (junction 434) : [index < 30]
    (default) -> (junction 431)
  state final = usb_final_check [function]
    (junction 438) -> (junction 435) : [(usb_send_status[0] & 0x15) == 0x15]
    (junction 436) -> (junction 433)
    (junction 435) -> (junction 436) : { final = 1; }
    (junction 438) -> (junction 433) : { final = 0; }
    (default) -> (junction 438) : { % VALID(bit0) STOP(bit2) ELP(bit4) check }
  state CLOSE/
    en:
    DISCONNECT;
    disconnect = 0;
  state OPEN/
    en:
    usb_function();
    disconnect = usb_final_check();
    du:
    usb_function();
    disconnect = usb_final_check();
  state usb_function [function]
    (default) -> (junction 447) : { usb_send_status = 0; usb_send_number = 0; usb_send_data = 0; disconnect = 0; }
    (junction 443) -> (junction 445)
    (junction 443) -> (junction 444) : [ScannerBuffer_Info[0] == FULL_UP]
    (junction 445) -> (junction 442) : { % 送るものが無い }
    (junction 444) -> (junction 454) : { % USB通信実行 usb_communication(0); init_buffer(0); COMUNICATION; }
    (junction 445) -> (junction 446) : [ScannerBuffer_Info[1] == FULL_UP]
    (junction 446) -> (junction 453) : { % USB通信実行 usb_communication(1); init_buffer(1); COMUNICATION; }
    (junction 450) -> (junction 449) : [ ScannerBuffer_Pnum[0] <= ScannerBuffer_Pnum[1] ]
    (junction 447) -> (junction 443)
    (junction 447) -> (junction 448) : [ScannerBuffer_Info[0] == FULL_UP && ScannerBuffer_Info[1] == FULL_UP]
    (junction 449) -> (junction 451) : { % USB通信実行 usb_communication(0); init_buffer(0); COMUNICATION; }
    (junction 450) -> (junction 452) : { % USB通信実行 usb_communication(1); init_buffer(1); COMUNICATION; }
    (junction 448) -> (junction 450)
    (junction 451) -> (junction 452)
    (junction 452) -> (junction 454)
    (junction 454) -> (junction 453)
    (junction 453) -> (junction 442)
  (default) -> OPEN
  OPEN -> CLOSE : [disconnect == 1]
  CLOSE -> OPEN : [disconnect == 0]
